VERSION 5.8 ;
BUSBITCHARS "[]" ;
DIVIDERCHAR "/" ;
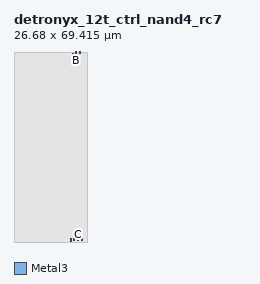
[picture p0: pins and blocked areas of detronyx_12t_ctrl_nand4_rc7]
MACRO detronyx_12t_ctrl_nand4_rc7
  CLASS BLOCK ;
  FOREIGN detronyx_12t_ctrl_nand4_rc7 0.000 0.000 ;
  ORIGIN 0.000 0.000 ;
  SIZE 26.680000 BY 69.415000 ;
  SYMMETRY X Y ;
  PIN VDD
    DIRECTION INOUT ;
    USE POWER ;
    PORT
      LAYER Metal3 ;
        RECT 21.200000 67.715000 21.560000 68.915000 ;
    END
  END VDD
  PIN VSS
    DIRECTION INOUT ;
    USE GROUND ;
    PORT
      LAYER Metal3 ;
        RECT 20.500000 0.200000 20.860000 1.400000 ;
    END
  END VSS
  PIN A
    DIRECTION INPUT ;
    USE SIGNAL ;
    PORT
      LAYER Metal3 ;
        RECT 21.900000 0.400000 22.260000 1.200000 ;
    END
  END A
  PIN B
    DIRECTION INPUT ;
    USE SIGNAL ;
    PORT
      LAYER Metal3 ;
        RECT 22.600000 68.815000 22.960000 69.615000 ;
    END
  END B
  PIN C
    DIRECTION INPUT ;
    USE SIGNAL ;
    PORT
      LAYER Metal3 ;
        RECT 23.300000 0.400000 23.660000 1.200000 ;
    END
  END C
  PIN D
    DIRECTION INPUT ;
    USE SIGNAL ;
    PORT
      LAYER Metal3 ;
        RECT 24.000000 68.815000 24.360000 69.615000 ;
    END
  END D
  PIN Y
    DIRECTION OUTPUT ;
    USE SIGNAL ;
    PORT
      LAYER Metal3 ;
        RECT 24.700000 0.400000 25.060000 1.200000 ;
    END
  END Y
  OBS
    LAYER Metal1 ;
      RECT 0.000000 0.000000 26.680000 69.415000 ;
    LAYER Metal2 ;
      RECT 0.000000 0.000000 26.680000 69.415000 ;
  END
END detronyx_12t_ctrl_nand4_rc7
END LIBRARY
